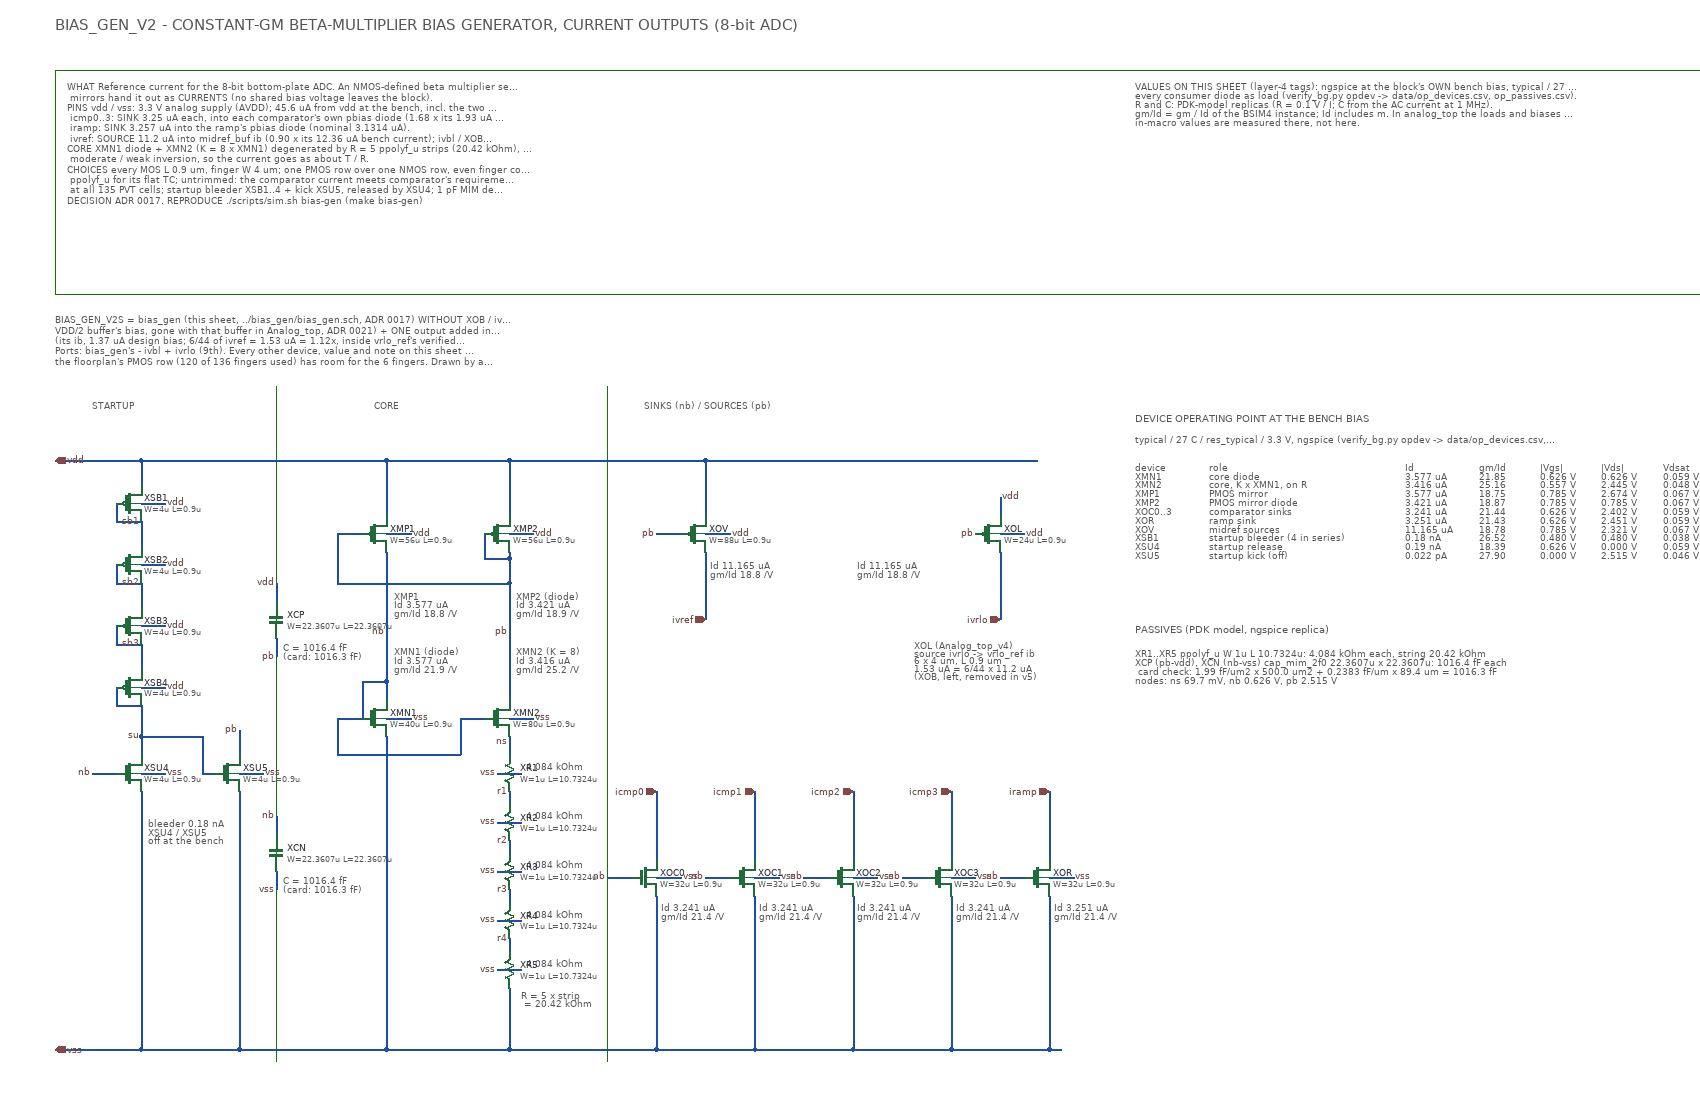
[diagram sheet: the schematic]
v {xschem version=3.4.8RC file_version=1.2}
G {}
K {}
V {}
S {}
E {}
T {BIAS_GEN_V2  -  CONSTANT-GM BETA-MULTIPLIER BIAS GENERATOR, CURRENT OUTPUTS (8-bit ADC)} 40 -1700 0 0 0.75 0.75 {}
T {WHAT  Reference current for the 8-bit bottom-plate ADC. An NMOS-defined beta multiplier sets one core current;
      mirrors hand it out as CURRENTS (no shared bias voltage leaves the block).
PINS  vdd / vss: 3.3 V analog supply (AVDD); 45.6 uA from vdd at the bench, incl. the two midref currents.
      icmp0..3: SINK 3.25 uA each, into each comparator's own pbias diode (1.68 x its 1.93 uA design bias, ADR 0017).
      iramp: SINK 3.257 uA into the ramp's pbias diode (nominal 3.1314 uA).
      ivref: SOURCE 11.2 uA into midref_buf ib (0.90 x its 12.36 uA bench current); ivbl / XOB removed (v5).
CORE  XMN1 diode + XMN2 (K = 8 x XMN1) degenerated by R = 5 ppolyf_u strips (20.42 kOhm), 1:1 PMOS mirror XMP1 / XMP2;
      moderate / weak inversion, so the current goes as about T / R.
CHOICES  every MOS L 0.9 um, finger W 4 um; one PMOS row over one NMOS row, even finger counts, common centroid;
      ppolyf_u for its flat TC; untrimmed: the comparator current meets comparator's requirement x (1 + 3 sigma)
      at all 135 PVT cells; startup bleeder XSB1..4 + kick XSU5, released by XSU4; 1 pF MIM decaps on pb and nb.
DECISION  ADR 0017.   REPRODUCE  ./scripts/sim.sh bias-gen  (make bias-gen)
NETLIST  bias_gen.spice, GENERATED by size_bg.py; this drawing by bias_gen_sch.py.} 60 -1600 0 0 0.42 0.42 {}
T {VALUES ON THIS SHEET (layer-4 tags): ngspice at the block's OWN bench bias, typical / 27 C / res_typical / 3.3 V,
every consumer diode as load (verify_bg.py opdev -> data/op_devices.csv, op_passives.csv).
R and C: PDK-model replicas (R = 0.1 V / I; C from the AC current at 1 MHz).
gm/Id = gm / Id of the BSIM4 instance; Id includes m. In analog_top the loads and biases differ:
in-macro values are measured there, not here.} 1800 -1600 0 0 0.36 0.36 {layer=8}
B 4 40 -1615 2790 -1250 {fill=false dash=4}
T {XMP1
Id 3.577 uA
gm/Id 18.8 /V} 592 -770 0 0 0.36 0.36 {layer=4}
T {XMP2 (diode)
Id 3.421 uA
gm/Id 18.9 /V} 792 -770 0 0 0.36 0.36 {layer=4}
T {XMN1 (diode)
Id 3.577 uA
gm/Id 21.9 /V} 592 -680 0 0 0.36 0.36 {layer=4}
T {XMN2 (K = 8)
Id 3.416 uA
gm/Id 25.2 /V} 792 -680 0 0 0.36 0.36 {layer=4}
T {4.084 kOhm} 808 -492 0 0 0.36 0.36 {layer=4}
T {4.084 kOhm} 808 -412 0 0 0.36 0.36 {layer=4}
T {4.084 kOhm} 808 -332 0 0 0.36 0.36 {layer=4}
T {4.084 kOhm} 808 -252 0 0 0.36 0.36 {layer=4}
T {4.084 kOhm} 808 -172 0 0 0.36 0.36 {layer=4}
T {R = 5 x strip
  = 20.42 kOhm} 800 -120 0 0 0.36 0.36 {layer=4}
T {C = 1016.4 fF
(card: 1016.3 fF)} 412 -686 0 0 0.36 0.36 {layer=4}
T {C = 1016.4 fF
(card: 1016.3 fF)} 412 -306 0 0 0.36 0.36 {layer=4}
T {Id 3.241 uA
gm/Id 21.4 /V} 1028 -262 0 0 0.36 0.36 {layer=4}
T {Id 3.241 uA
gm/Id 21.4 /V} 1188 -262 0 0 0.36 0.36 {layer=4}
T {Id 3.241 uA
gm/Id 21.4 /V} 1348 -262 0 0 0.36 0.36 {layer=4}
T {Id 3.241 uA
gm/Id 21.4 /V} 1508 -262 0 0 0.36 0.36 {layer=4}
T {Id 3.251 uA
gm/Id 21.4 /V} 1668 -262 0 0 0.36 0.36 {layer=4}
T {Id 11.165 uA
gm/Id 18.8 /V} 1108 -820 0 0 0.36 0.36 {layer=4}
T {Id 11.165 uA
gm/Id 18.8 /V} 1348 -820 0 0 0.36 0.36 {layer=4}
T {bleeder 0.18 nA
XSU4 / XSU5
off at the bench} 192 -400 0 0 0.36 0.36 {layer=4}
T {DEVICE OPERATING POINT AT THE BENCH BIAS} 1800 -1060 0 0 0.5 0.5 {layer=8}
T {typical / 27 C / res_typical / 3.3 V, ngspice (verify_bg.py opdev -> data/op_devices.csv, op_passives.csv)} 1800 -1026 0 0 0.32 0.32 {}
T {device
XMN1
XMN2
XMP1
XMP2
XOC0..3
XOR
XOV
XSB1
XSU4
XSU5} 1800 -980 0 0 0.36 0.36 {}
T {role
core diode
core, K x XMN1, on R
PMOS mirror
PMOS mirror diode
comparator sinks
ramp sink
midref sources
startup bleeder (4 in series)
startup release
startup kick (off)} 1920 -980 0 0 0.36 0.36 {layer=4}
T {Id
3.577 uA
3.416 uA
3.577 uA
3.421 uA
3.241 uA
3.251 uA
11.165 uA
0.18 nA
0.19 nA
0.022 pA} 2240 -980 0 0 0.36 0.36 {layer=4}
T {gm/Id
21.85
25.16
18.75
18.87
21.44
21.43
18.78
26.52
18.39
27.90} 2360 -980 0 0 0.36 0.36 {layer=4}
T {|Vgs|
0.626 V
0.557 V
0.785 V
0.785 V
0.626 V
0.626 V
0.785 V
0.480 V
0.626 V
0.000 V} 2460 -980 0 0 0.36 0.36 {layer=4}
T {|Vds|
0.626 V
2.445 V
2.674 V
0.785 V
2.402 V
2.451 V
2.321 V
0.480 V
0.000 V
2.515 V} 2560 -980 0 0 0.36 0.36 {layer=4}
T {Vdsat
0.059 V
0.048 V
0.067 V
0.067 V
0.059 V
0.059 V
0.067 V
0.038 V
0.059 V
0.046 V} 2660 -980 0 0 0.36 0.36 {layer=4}
T {PASSIVES (PDK model, ngspice replica)} 1800 -716 0 0 0.5 0.5 {layer=8}
T {XR1..XR5  ppolyf_u W 1u L 10.7324u: 4.084 kOhm each, string 20.42 kOhm
XCP (pb-vdd), XCN (nb-vss)  cap_mim_2f0 22.3607u x 22.3607u: 1016.4 fF each
   card check: 1.99 fF/um2 x 500.0 um2 + 0.2383 fF/um x 89.4 um = 1016.3 fF
nodes: ns 69.7 mV, nb 0.626 V, pb 2.515 V} 1800 -676 0 0 0.36 0.36 {layer=4}
T {STARTUP} 100 -1080 0 0 0.4 0.4 {}
T {CORE} 560 -1080 0 0 0.4 0.4 {}
T {SINKS (nb)  /  SOURCES (pb)} 1000 -1080 0 0 0.4 0.4 {}
L 4 400 -1100 400 0 {dash=6}
L 4 940 -1100 940 0 {dash=6}
N 180 -980 180 -940 {lab=vdd}
N 140 -910 140 -880 {lab=sb1}
N 140 -880 180 -880 {lab=sb1}
N 180 -910 220 -910 {lab=vdd}
N 180 -880 180 -840 {lab=sb1}
N 140 -810 140 -780 {lab=sb2}
N 140 -780 180 -780 {lab=sb2}
N 180 -810 220 -810 {lab=vdd}
N 180 -780 180 -740 {lab=sb2}
N 140 -710 140 -680 {lab=sb3}
N 140 -680 180 -680 {lab=sb3}
N 180 -710 220 -710 {lab=vdd}
N 180 -680 180 -640 {lab=sb3}
N 140 -610 140 -580 {lab=su}
N 140 -580 180 -580 {lab=su}
N 180 -610 220 -610 {lab=vdd}
N 180 -580 180 -530 {lab=su}
N 180 -530 180 -500 {lab=su}
N 180 -440 180 -20 {lab=vss}
N 100 -470 140 -470 {lab=nb}
N 180 -470 220 -470 {lab=vss}
N 180 -530 280 -530 {lab=su}
N 280 -530 280 -470 {lab=su}
N 280 -470 300 -470 {lab=su}
N 340 -440 340 -20 {lab=vss}
N 340 -540 340 -500 {lab=pb}
N 340 -470 380 -470 {lab=vss}
N 580 -980 580 -890 {lab=vdd}
N 780 -980 780 -890 {lab=vdd}
N 580 -830 580 -700 {lab=nb}
N 580 -700 580 -620 {lab=nb}
N 580 -620 580 -590 {lab=nb}
N 780 -830 780 -820 {lab=pb}
N 780 -820 780 -780 {lab=pb}
N 780 -780 780 -700 {lab=pb}
N 780 -700 780 -590 {lab=pb}
N 740 -860 740 -820 {lab=pb}
N 740 -820 780 -820 {lab=pb}
N 500 -860 540 -860 {lab=pb}
N 500 -860 500 -780 {lab=pb}
N 500 -780 780 -780 {lab=pb}
N 540 -620 540 -560 {lab=nb}
N 540 -620 580 -620 {lab=nb}
N 500 -560 540 -560 {lab=nb}
N 500 -560 500 -500 {lab=nb}
N 500 -500 700 -500 {lab=nb}
N 700 -560 700 -500 {lab=nb}
N 700 -560 740 -560 {lab=nb}
N 580 -530 580 -20 {lab=vss}
N 580 -860 620 -860 {lab=vdd}
N 780 -860 820 -860 {lab=vdd}
N 580 -560 620 -560 {lab=vss}
N 780 -560 820 -560 {lab=vss}
N 780 -530 780 -520 {lab=ns}
N 780 -520 780 -500 {lab=ns}
N 760 -470 800 -470 {lab=vss}
N 780 -440 780 -420 {lab=r1}
N 760 -390 800 -390 {lab=vss}
N 780 -360 780 -340 {lab=r2}
N 760 -310 800 -310 {lab=vss}
N 780 -280 780 -260 {lab=r3}
N 760 -230 800 -230 {lab=vss}
N 780 -200 780 -180 {lab=r4}
N 760 -150 800 -150 {lab=vss}
N 780 -120 780 -20 {lab=vss}
N 400 -780 400 -750 {lab=vdd}
N 400 -690 400 -660 {lab=pb}
N 400 -400 400 -370 {lab=nb}
N 400 -310 400 -280 {lab=vss}
N 1020 -440 1020 -330 {lab=icmp0}
N 940 -300 980 -300 {lab=nb}
N 1020 -270 1020 -20 {lab=vss}
N 1020 -300 1060 -300 {lab=vss}
N 1180 -440 1180 -330 {lab=icmp1}
N 1100 -300 1140 -300 {lab=nb}
N 1180 -270 1180 -20 {lab=vss}
N 1180 -300 1220 -300 {lab=vss}
N 1340 -440 1340 -330 {lab=icmp2}
N 1260 -300 1300 -300 {lab=nb}
N 1340 -270 1340 -20 {lab=vss}
N 1340 -300 1380 -300 {lab=vss}
N 1500 -440 1500 -330 {lab=icmp3}
N 1420 -300 1460 -300 {lab=nb}
N 1500 -270 1500 -20 {lab=vss}
N 1500 -300 1540 -300 {lab=vss}
N 1660 -440 1660 -330 {lab=iramp}
N 1580 -300 1620 -300 {lab=nb}
N 1660 -270 1660 -20 {lab=vss}
N 1660 -300 1700 -300 {lab=vss}
N 1100 -830 1100 -720 {lab=ivref}
N 1020 -860 1060 -860 {lab=pb}
N 1100 -980 1100 -890 {lab=vdd}
N 1100 -860 1140 -860 {lab=vdd}
N 40 -980 180 -980 {lab=vdd}
N 180 -980 580 -980 {lab=vdd}
N 580 -980 780 -980 {lab=vdd}
N 780 -980 1100 -980 {lab=vdd}
N 1100 -980 1340 -980 {lab=vdd}
N 1340 -980 1640 -980 {lab=vdd}
N 40 -20 180 -20 {lab=vss}
N 180 -20 340 -20 {lab=vss}
N 340 -20 580 -20 {lab=vss}
N 580 -20 780 -20 {lab=vss}
N 780 -20 1020 -20 {lab=vss}
N 1020 -20 1180 -20 {lab=vss}
N 1180 -20 1340 -20 {lab=vss}
N 1340 -20 1500 -20 {lab=vss}
N 1500 -20 1660 -20 {lab=vss}
N 1660 -20 1680 -20 {lab=vss}
C {devices/iopin.sym} 40 -980 0 1 {name=pvdd lab=vdd sim_pinnumber=1}
C {devices/iopin.sym} 40 -20 0 1 {name=pvss lab=vss sim_pinnumber=2}
C {symbols/pfet_03v3.sym} 160 -910 0 0 {name=XSB1
L=0.9u
W=4u
nf=1
m=1
ad=0.72p
pd=8.36u
as=0.72p
ps=8.36u
nrd=0.045
nrs=0.045
model=pfet_03v3
spiceprefix=""
format="@name @pinlist @model L=@L W=@W nf=@nf m=@m ad=@ad pd=@pd as=@as ps=@ps nrd=@nrd nrs=@nrs"}
C {devices/lab_pin.sym} 220 -910 0 1 {name=l1 sig_type=std_logic lab=vdd}
C {devices/lab_wire.sym} 180 -880 0 0 {name=l2 sig_type=std_logic lab=sb1}
C {symbols/pfet_03v3.sym} 160 -810 0 0 {name=XSB2
L=0.9u
W=4u
nf=1
m=1
ad=0.72p
pd=8.36u
as=0.72p
ps=8.36u
nrd=0.045
nrs=0.045
model=pfet_03v3
spiceprefix=""
format="@name @pinlist @model L=@L W=@W nf=@nf m=@m ad=@ad pd=@pd as=@as ps=@ps nrd=@nrd nrs=@nrs"}
C {devices/lab_pin.sym} 220 -810 0 1 {name=l3 sig_type=std_logic lab=vdd}
C {devices/lab_wire.sym} 180 -780 0 0 {name=l4 sig_type=std_logic lab=sb2}
C {symbols/pfet_03v3.sym} 160 -710 0 0 {name=XSB3
L=0.9u
W=4u
nf=1
m=1
ad=0.72p
pd=8.36u
as=0.72p
ps=8.36u
nrd=0.045
nrs=0.045
model=pfet_03v3
spiceprefix=""
format="@name @pinlist @model L=@L W=@W nf=@nf m=@m ad=@ad pd=@pd as=@as ps=@ps nrd=@nrd nrs=@nrs"}
C {devices/lab_pin.sym} 220 -710 0 1 {name=l5 sig_type=std_logic lab=vdd}
C {devices/lab_wire.sym} 180 -680 0 0 {name=l6 sig_type=std_logic lab=sb3}
C {symbols/pfet_03v3.sym} 160 -610 0 0 {name=XSB4
L=0.9u
W=4u
nf=1
m=1
ad=0.72p
pd=8.36u
as=0.72p
ps=8.36u
nrd=0.045
nrs=0.045
model=pfet_03v3
spiceprefix=""
format="@name @pinlist @model L=@L W=@W nf=@nf m=@m ad=@ad pd=@pd as=@as ps=@ps nrd=@nrd nrs=@nrs"}
C {devices/lab_pin.sym} 220 -610 0 1 {name=l7 sig_type=std_logic lab=vdd}
C {symbols/nfet_03v3.sym} 160 -470 0 0 {name=XSU4
L=0.9u
W=4u
nf=1
m=1
ad=0.72p
pd=8.36u
as=0.72p
ps=8.36u
nrd=0.045
nrs=0.045
model=nfet_03v3
spiceprefix=""
format="@name @pinlist @model L=@L W=@W nf=@nf m=@m ad=@ad pd=@pd as=@as ps=@ps nrd=@nrd nrs=@nrs"}
C {devices/lab_pin.sym} 100 -470 0 0 {name=l8 sig_type=std_logic lab=nb}
C {devices/lab_pin.sym} 220 -470 0 1 {name=l9 sig_type=std_logic lab=vss}
C {symbols/nfet_03v3.sym} 320 -470 0 0 {name=XSU5
L=0.9u
W=4u
nf=1
m=1
ad=0.72p
pd=8.36u
as=0.72p
ps=8.36u
nrd=0.045
nrs=0.045
model=nfet_03v3
spiceprefix=""
format="@name @pinlist @model L=@L W=@W nf=@nf m=@m ad=@ad pd=@pd as=@as ps=@ps nrd=@nrd nrs=@nrs"}
C {devices/lab_pin.sym} 340 -540 0 0 {name=l10 sig_type=std_logic lab=pb}
C {devices/lab_pin.sym} 380 -470 0 1 {name=l11 sig_type=std_logic lab=vss}
C {devices/lab_wire.sym} 180 -530 0 0 {name=l12 sig_type=std_logic lab=su}
C {symbols/pfet_03v3.sym} 560 -860 0 0 {name=XMP1
L=0.9u
W=56u
nf=14
m=1
ad=5.04p
pd=58.52u
as=5.76p
ps=66.88u
nrd=0.003214
nrs=0.003214
model=pfet_03v3
spiceprefix=""
format="@name @pinlist @model L=@L W=@W nf=@nf m=@m ad=@ad pd=@pd as=@as ps=@ps nrd=@nrd nrs=@nrs"}
C {symbols/pfet_03v3.sym} 760 -860 0 0 {name=XMP2
L=0.9u
W=56u
nf=14
m=1
ad=5.04p
pd=58.52u
as=5.76p
ps=66.88u
nrd=0.003214
nrs=0.003214
model=pfet_03v3
spiceprefix=""
format="@name @pinlist @model L=@L W=@W nf=@nf m=@m ad=@ad pd=@pd as=@as ps=@ps nrd=@nrd nrs=@nrs"}
C {symbols/nfet_03v3.sym} 560 -560 0 0 {name=XMN1
L=0.9u
W=40u
nf=10
m=1
ad=3.6p
pd=41.8u
as=4.32p
ps=50.16u
nrd=0.0045
nrs=0.0045
model=nfet_03v3
spiceprefix=""
format="@name @pinlist @model L=@L W=@W nf=@nf m=@m ad=@ad pd=@pd as=@as ps=@ps nrd=@nrd nrs=@nrs"}
C {symbols/nfet_03v3.sym} 760 -560 0 0 {name=XMN2
L=0.9u
W=80u
nf=20
m=4
ad=7.2p
pd=83.6u
as=7.92p
ps=91.96u
nrd=0.00225
nrs=0.00225
model=nfet_03v3
spiceprefix=""
format="@name @pinlist @model L=@L W=@W nf=@nf m=@m ad=@ad pd=@pd as=@as ps=@ps nrd=@nrd nrs=@nrs"}
C {devices/lab_wire.sym} 580 -700 0 0 {name=l13 sig_type=std_logic lab=nb}
C {devices/lab_wire.sym} 780 -700 0 0 {name=l14 sig_type=std_logic lab=pb}
C {devices/lab_pin.sym} 620 -860 0 1 {name=l15 sig_type=std_logic lab=vdd}
C {devices/lab_pin.sym} 820 -860 0 1 {name=l16 sig_type=std_logic lab=vdd}
C {devices/lab_pin.sym} 620 -560 0 1 {name=l17 sig_type=std_logic lab=vss}
C {devices/lab_pin.sym} 820 -560 0 1 {name=l18 sig_type=std_logic lab=vss}
C {symbols/ppolyf_u.sym} 780 -470 2 0 {name=XR1
W=1u
L=10.7324u
model=ppolyf_u
spiceprefix=""
m=1}
C {devices/lab_pin.sym} 760 -470 0 0 {name=l19 sig_type=std_logic lab=vss}
C {devices/lab_wire.sym} 780 -440 0 0 {name=l20 sig_type=std_logic lab=r1}
C {symbols/ppolyf_u.sym} 780 -390 2 0 {name=XR2
W=1u
L=10.7324u
model=ppolyf_u
spiceprefix=""
m=1}
C {devices/lab_pin.sym} 760 -390 0 0 {name=l21 sig_type=std_logic lab=vss}
C {devices/lab_wire.sym} 780 -360 0 0 {name=l22 sig_type=std_logic lab=r2}
C {symbols/ppolyf_u.sym} 780 -310 2 0 {name=XR3
W=1u
L=10.7324u
model=ppolyf_u
spiceprefix=""
m=1}
C {devices/lab_pin.sym} 760 -310 0 0 {name=l23 sig_type=std_logic lab=vss}
C {devices/lab_wire.sym} 780 -280 0 0 {name=l24 sig_type=std_logic lab=r3}
C {symbols/ppolyf_u.sym} 780 -230 2 0 {name=XR4
W=1u
L=10.7324u
model=ppolyf_u
spiceprefix=""
m=1}
C {devices/lab_pin.sym} 760 -230 0 0 {name=l25 sig_type=std_logic lab=vss}
C {devices/lab_wire.sym} 780 -200 0 0 {name=l26 sig_type=std_logic lab=r4}
C {symbols/ppolyf_u.sym} 780 -150 2 0 {name=XR5
W=1u
L=10.7324u
model=ppolyf_u
spiceprefix=""
m=1}
C {devices/lab_pin.sym} 760 -150 0 0 {name=l27 sig_type=std_logic lab=vss}
C {devices/lab_wire.sym} 780 -520 0 0 {name=l28 sig_type=std_logic lab=ns}
C {symbols/cap_mim_2f0fF.sym} 400 -720 0 0 {name=XCP W=22.3607u L=22.3607u model=cap_mim_2f0_m4m5_noshield spiceprefix="" m=1}
C {devices/lab_pin.sym} 400 -780 0 0 {name=l29 sig_type=std_logic lab=vdd}
C {devices/lab_pin.sym} 400 -660 0 0 {name=l30 sig_type=std_logic lab=pb}
C {symbols/cap_mim_2f0fF.sym} 400 -340 0 0 {name=XCN W=22.3607u L=22.3607u model=cap_mim_2f0_m4m5_noshield spiceprefix="" m=1}
C {devices/lab_pin.sym} 400 -400 0 0 {name=l31 sig_type=std_logic lab=nb}
C {devices/lab_pin.sym} 400 -280 0 0 {name=l32 sig_type=std_logic lab=vss}
C {symbols/nfet_03v3.sym} 1000 -300 0 0 {name=XOC0
L=0.9u
W=32u
nf=8
m=1
ad=2.88p
pd=33.44u
as=3.6p
ps=41.8u
nrd=0.005625
nrs=0.005625
model=nfet_03v3
spiceprefix=""
format="@name @pinlist @model L=@L W=@W nf=@nf m=@m ad=@ad pd=@pd as=@as ps=@ps nrd=@nrd nrs=@nrs"}
C {devices/iopin.sym} 1020 -440 0 0 {name=picmp0 lab=icmp0 sim_pinnumber=3}
C {devices/lab_pin.sym} 940 -300 0 0 {name=l33 sig_type=std_logic lab=nb}
C {devices/lab_pin.sym} 1060 -300 0 1 {name=l34 sig_type=std_logic lab=vss}
C {symbols/nfet_03v3.sym} 1160 -300 0 0 {name=XOC1
L=0.9u
W=32u
nf=8
m=1
ad=2.88p
pd=33.44u
as=3.6p
ps=41.8u
nrd=0.005625
nrs=0.005625
model=nfet_03v3
spiceprefix=""
format="@name @pinlist @model L=@L W=@W nf=@nf m=@m ad=@ad pd=@pd as=@as ps=@ps nrd=@nrd nrs=@nrs"}
C {devices/iopin.sym} 1180 -440 0 0 {name=picmp1 lab=icmp1 sim_pinnumber=4}
C {devices/lab_pin.sym} 1100 -300 0 0 {name=l35 sig_type=std_logic lab=nb}
C {devices/lab_pin.sym} 1220 -300 0 1 {name=l36 sig_type=std_logic lab=vss}
C {symbols/nfet_03v3.sym} 1320 -300 0 0 {name=XOC2
L=0.9u
W=32u
nf=8
m=1
ad=2.88p
pd=33.44u
as=3.6p
ps=41.8u
nrd=0.005625
nrs=0.005625
model=nfet_03v3
spiceprefix=""
format="@name @pinlist @model L=@L W=@W nf=@nf m=@m ad=@ad pd=@pd as=@as ps=@ps nrd=@nrd nrs=@nrs"}
C {devices/iopin.sym} 1340 -440 0 0 {name=picmp2 lab=icmp2 sim_pinnumber=5}
C {devices/lab_pin.sym} 1260 -300 0 0 {name=l37 sig_type=std_logic lab=nb}
C {devices/lab_pin.sym} 1380 -300 0 1 {name=l38 sig_type=std_logic lab=vss}
C {symbols/nfet_03v3.sym} 1480 -300 0 0 {name=XOC3
L=0.9u
W=32u
nf=8
m=1
ad=2.88p
pd=33.44u
as=3.6p
ps=41.8u
nrd=0.005625
nrs=0.005625
model=nfet_03v3
spiceprefix=""
format="@name @pinlist @model L=@L W=@W nf=@nf m=@m ad=@ad pd=@pd as=@as ps=@ps nrd=@nrd nrs=@nrs"}
C {devices/iopin.sym} 1500 -440 0 0 {name=picmp3 lab=icmp3 sim_pinnumber=6}
C {devices/lab_pin.sym} 1420 -300 0 0 {name=l39 sig_type=std_logic lab=nb}
C {devices/lab_pin.sym} 1540 -300 0 1 {name=l40 sig_type=std_logic lab=vss}
C {symbols/nfet_03v3.sym} 1640 -300 0 0 {name=XOR
L=0.9u
W=32u
nf=8
m=1
ad=2.88p
pd=33.44u
as=3.6p
ps=41.8u
nrd=0.005625
nrs=0.005625
model=nfet_03v3
spiceprefix=""
format="@name @pinlist @model L=@L W=@W nf=@nf m=@m ad=@ad pd=@pd as=@as ps=@ps nrd=@nrd nrs=@nrs"}
C {devices/iopin.sym} 1660 -440 0 0 {name=piramp lab=iramp sim_pinnumber=7}
C {devices/lab_pin.sym} 1580 -300 0 0 {name=l41 sig_type=std_logic lab=nb}
C {devices/lab_pin.sym} 1700 -300 0 1 {name=l42 sig_type=std_logic lab=vss}
C {symbols/pfet_03v3.sym} 1080 -860 0 0 {name=XOV
L=0.9u
W=88u
nf=22
m=2
ad=7.92p
pd=91.96u
as=8.64p
ps=100.3u
nrd=0.002045
nrs=0.002045
model=pfet_03v3
spiceprefix=""
format="@name @pinlist @model L=@L W=@W nf=@nf m=@m ad=@ad pd=@pd as=@as ps=@ps nrd=@nrd nrs=@nrs"}
C {devices/iopin.sym} 1100 -720 0 0 {name=pivref lab=ivref sim_pinnumber=8}
C {devices/lab_pin.sym} 1020 -860 0 0 {name=l43 sig_type=std_logic lab=pb}
C {devices/lab_pin.sym} 1140 -860 0 1 {name=l44 sig_type=std_logic lab=vdd}
C {devices/title.sym} 0 140 0 0 {name=l99 author="ASIC R&D - mixed_signal/bias_gen - bias_gen"}
C {symbols/pfet_03v3.sym} 1560 -860 0 0 {name=XOL
L=0.9u
W=24u
nf=6
m=1
ad=2.16p
pd=25.08u
as=2.88p
ps=33.44u
nrd=0.0075
nrs=0.0075
model=pfet_03v3
spiceprefix=""
format="@name @pinlist @model L=@L W=@W nf=@nf m=@m ad=@ad pd=@pd as=@as ps=@ps nrd=@nrd nrs=@nrs"}
C {devices/lab_pin.sym} 1540 -860 0 0 {name=lv4_1 sig_type=std_logic lab=pb}
N 1580 -890 1580 -920 {lab=vdd}
C {devices/lab_pin.sym} 1580 -920 0 1 {name=lv4_2 sig_type=std_logic lab=vdd}
N 1580 -860 1620 -860 {lab=vdd}
C {devices/lab_pin.sym} 1620 -860 0 1 {name=lv4_3 sig_type=std_logic lab=vdd}
N 1580 -830 1580 -720 {lab=ivrlo}
C {devices/iopin.sym} 1580 -720 0 0 {name=pivrlo lab=ivrlo sim_pinnumber=9}
T {XOL  (Analog_top_v4)
source ivrlo -> vrlo_ref ib
6 x 4 um, L 0.9 um
1.53 uA = 6/44 x 11.2 uA
(XOB, left, removed in v5)} 1440 -690 0 0 0.32 0.32 {layer=13}
T {BIAS_GEN_V2S = bias_gen (this sheet, ../bias_gen/bias_gen.sch, ADR 0017) WITHOUT XOB / ivbl (the second
VDD/2 buffer's bias, gone with that buffer in Analog_top, ADR 0021) + ONE output added in Analog_top_v4: XOL, 6 fingers of the 4 um x 0.9 um PMOS on pb, SOURCES ivrlo into vrlo_ref's NMOS diode
(its ib, 1.37 uA design bias; 6/44 of ivref = 1.53 uA = 1.12x, inside vrlo_ref's verified 0.69-1.77x span).
Ports: bias_gen's - ivbl + ivrlo (9th). Every other device, value and note on this sheet is bias_gen's;
the floorplan's PMOS row (120 of 136 fingers used) has room for the 6 fingers. Drawn by analog_top_sch.py.} 40 -1220 0 0 0.42 0.42 {layer=4}
